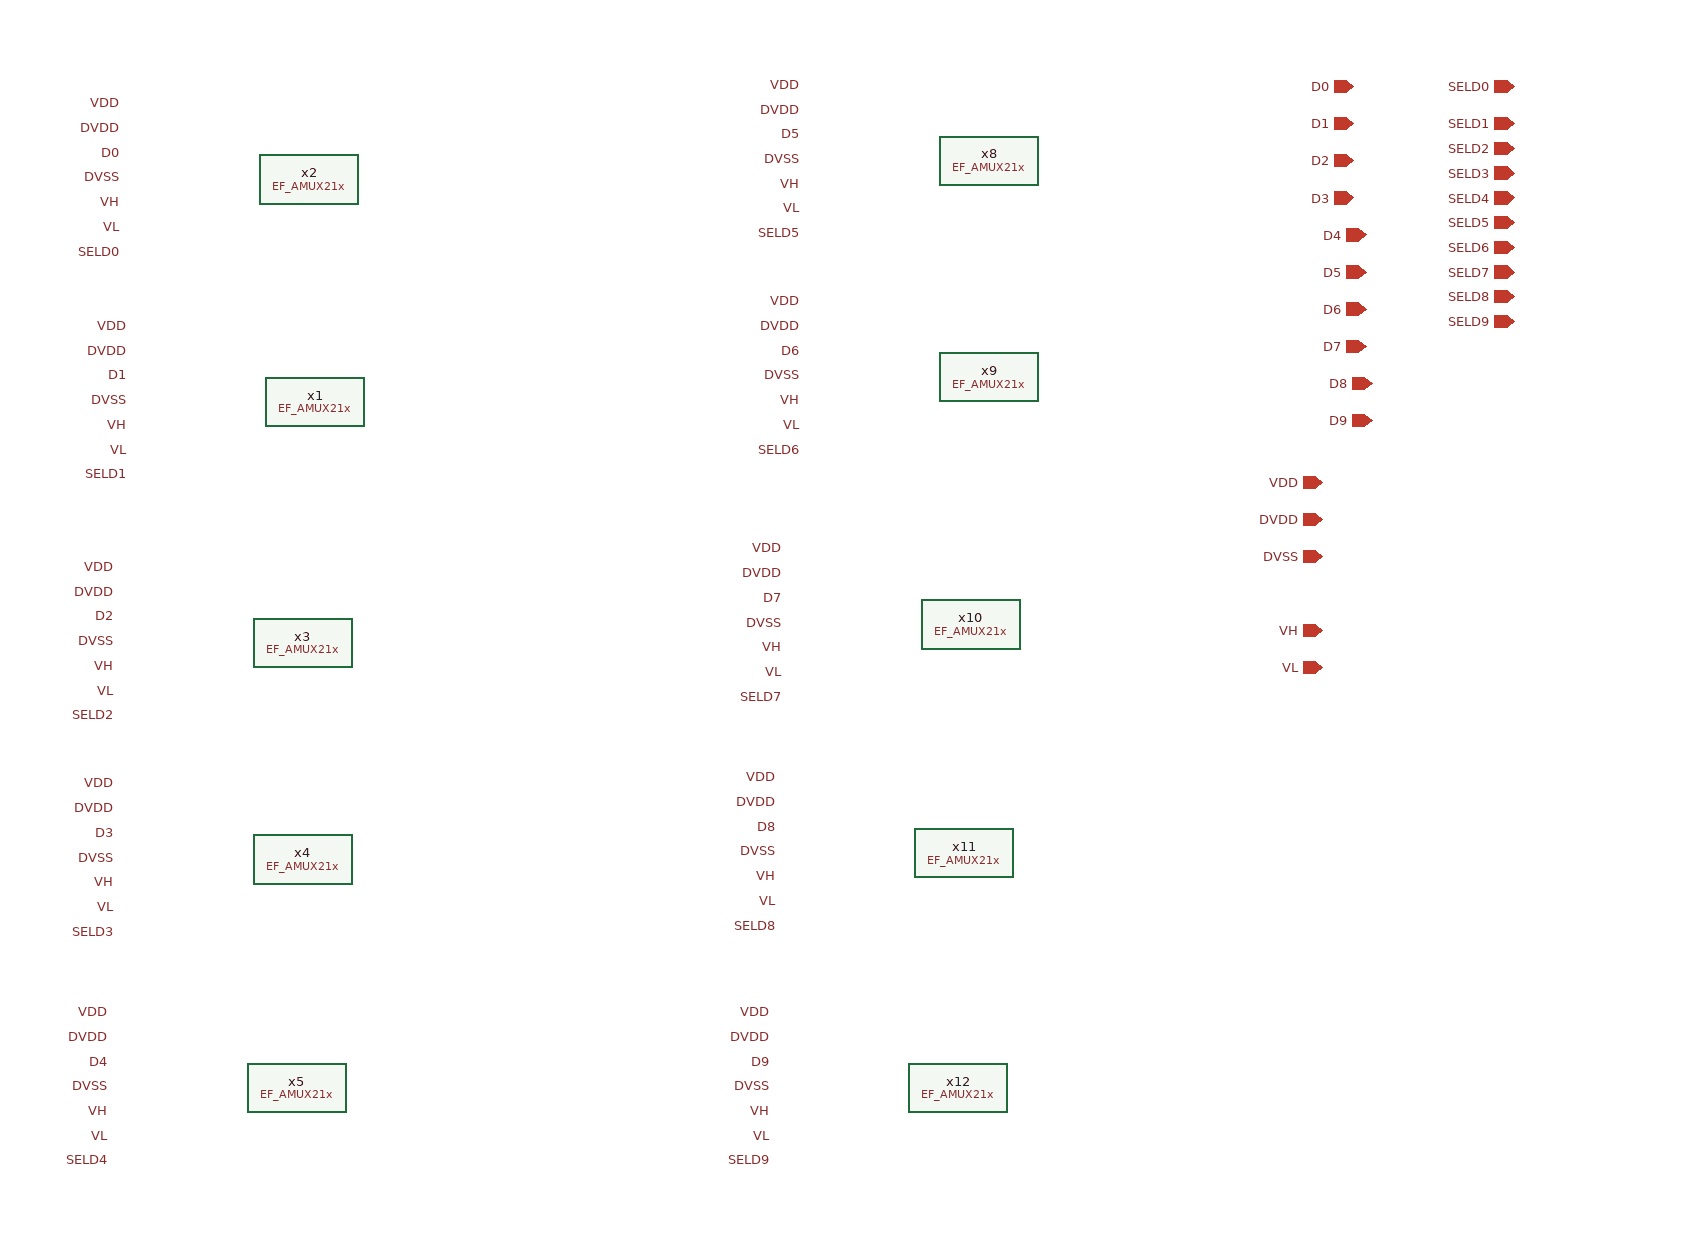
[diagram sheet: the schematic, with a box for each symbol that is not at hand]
v {xschem version=3.1.0 file_version=1.2
}
G {}
K {}
V {}
S {}
E {}
C {devices/lab_pin.sym} 1120 -965 0 0 {name=p6 sig_type=std_logic lab=VDD}
C {devices/lab_pin.sym} 1120 -945 0 0 {name=p8 sig_type=std_logic lab=DVDD}
C {Project/Package_IP/package_EF_ADCS1008NC/EF_ADCS1008NC/spice/xschem/EF_AMUX21x.sym} 1270 -905 0 0 {name=x2}
C {devices/lab_pin.sym} 1120 -925 0 0 {name=p17 sig_type=std_logic lab=D0}
C {devices/lab_pin.sym} 1120 -885 0 0 {name=p23 sig_type=std_logic lab=VH}
C {devices/lab_pin.sym} 1120 -845 0 0 {name=p11 sig_type=std_logic lab=SELD0}
C {devices/lab_pin.sym} 1120 -905 0 0 {name=p19 sig_type=std_logic lab=DVSS}
C {devices/lab_pin.sym} 1120 -865 0 0 {name=p22 sig_type=std_logic lab=VL}
C {devices/iopin.sym} 2090 -660 0 0 {name=p32 lab=VDD}
C {devices/iopin.sym} 2090 -630 0 0 {name=p33 lab=DVDD}
C {devices/iopin.sym} 2090 -600 0 0 {name=p34 lab=DVSS}
C {devices/iopin.sym} 2090 -540 0 0 {name=p36 lab=VH}
C {devices/lab_pin.sym} 1125 -785 0 0 {name=p12 sig_type=std_logic lab=VDD}
C {devices/lab_pin.sym} 1125 -765 0 0 {name=p13 sig_type=std_logic lab=DVDD}
C {Project/Package_IP/package_EF_ADCS1008NC/EF_ADCS1008NC/spice/xschem/EF_AMUX21x.sym} 1275 -725 0 0 {name=x1}
C {devices/lab_pin.sym} 1125 -745 0 0 {name=p14 sig_type=std_logic lab=D1}
C {devices/lab_pin.sym} 1125 -665 0 0 {name=p18 sig_type=std_logic lab=SELD1}
C {devices/lab_pin.sym} 1125 -725 0 0 {name=p20 sig_type=std_logic lab=DVSS}
C {devices/lab_pin.sym} 1125 -705 0 0 {name=p15 sig_type=std_logic lab=VH}
C {devices/lab_pin.sym} 1125 -685 0 0 {name=p26 sig_type=std_logic lab=VL}
C {devices/iopin.sym} 2090 -510 0 0 {name=p4 lab=VL}
C {devices/lab_pin.sym} 1115 -590 0 0 {name=p21 sig_type=std_logic lab=VDD}
C {devices/lab_pin.sym} 1115 -570 0 0 {name=p24 sig_type=std_logic lab=DVDD}
C {Project/Package_IP/package_EF_ADCS1008NC/EF_ADCS1008NC/spice/xschem/EF_AMUX21x.sym} 1265 -530 0 0 {name=x3}
C {devices/lab_pin.sym} 1115 -550 0 0 {name=p25 sig_type=std_logic lab=D2}
C {devices/lab_pin.sym} 1115 -470 0 0 {name=p28 sig_type=std_logic lab=SELD2}
C {devices/lab_pin.sym} 1115 -530 0 0 {name=p29 sig_type=std_logic lab=DVSS}
C {devices/lab_pin.sym} 1115 -510 0 0 {name=p5 sig_type=std_logic lab=VH}
C {devices/lab_pin.sym} 1115 -490 0 0 {name=p9 sig_type=std_logic lab=VL}
C {devices/lab_pin.sym} 1115 -415 0 0 {name=p7 sig_type=std_logic lab=VDD}
C {devices/lab_pin.sym} 1115 -395 0 0 {name=p10 sig_type=std_logic lab=DVDD}
C {Project/Package_IP/package_EF_ADCS1008NC/EF_ADCS1008NC/spice/xschem/EF_AMUX21x.sym} 1265 -355 0 0 {name=x4}
C {devices/lab_pin.sym} 1115 -375 0 0 {name=p30 sig_type=std_logic lab=D3}
C {devices/lab_pin.sym} 1115 -295 0 0 {name=p31 sig_type=std_logic lab=SELD3}
C {devices/lab_pin.sym} 1115 -355 0 0 {name=p35 sig_type=std_logic lab=DVSS}
C {devices/lab_pin.sym} 1115 -335 0 0 {name=p38 sig_type=std_logic lab=VH}
C {devices/lab_pin.sym} 1115 -315 0 0 {name=p39 sig_type=std_logic lab=VL}
C {devices/lab_pin.sym} 1110 -230 0 0 {name=p44 sig_type=std_logic lab=VDD}
C {devices/lab_pin.sym} 1110 -210 0 0 {name=p45 sig_type=std_logic lab=DVDD}
C {Project/Package_IP/package_EF_ADCS1008NC/EF_ADCS1008NC/spice/xschem/EF_AMUX21x.sym} 1260 -170 0 0 {name=x5}
C {devices/lab_pin.sym} 1110 -190 0 0 {name=p46 sig_type=std_logic lab=D4}
C {devices/lab_pin.sym} 1110 -110 0 0 {name=p47 sig_type=std_logic lab=SELD4}
C {devices/lab_pin.sym} 1110 -170 0 0 {name=p48 sig_type=std_logic lab=DVSS}
C {devices/lab_pin.sym} 1110 -150 0 0 {name=p49 sig_type=std_logic lab=VH}
C {devices/lab_pin.sym} 1110 -130 0 0 {name=p50 sig_type=std_logic lab=VL}
C {devices/lab_pin.sym} 1670 -980 0 0 {name=p74 sig_type=std_logic lab=VDD}
C {devices/lab_pin.sym} 1670 -960 0 0 {name=p75 sig_type=std_logic lab=DVDD}
C {Project/Package_IP/package_EF_ADCS1008NC/EF_ADCS1008NC/spice/xschem/EF_AMUX21x.sym} 1820 -920 0 0 {name=x8}
C {devices/lab_pin.sym} 1670 -940 0 0 {name=p76 sig_type=std_logic lab=D5}
C {devices/lab_pin.sym} 1670 -860 0 0 {name=p77 sig_type=std_logic lab=SELD5}
C {devices/lab_pin.sym} 1670 -920 0 0 {name=p78 sig_type=std_logic lab=DVSS}
C {devices/lab_pin.sym} 1670 -805 0 0 {name=p86 sig_type=std_logic lab=VDD}
C {devices/lab_pin.sym} 1670 -785 0 0 {name=p87 sig_type=std_logic lab=DVDD}
C {Project/Package_IP/package_EF_ADCS1008NC/EF_ADCS1008NC/spice/xschem/EF_AMUX21x.sym} 1820 -745 0 0 {name=x9}
C {devices/lab_pin.sym} 1670 -765 0 0 {name=p88 sig_type=std_logic lab=D6}
C {devices/lab_pin.sym} 1670 -685 0 0 {name=p89 sig_type=std_logic lab=SELD6}
C {devices/lab_pin.sym} 1670 -745 0 0 {name=p90 sig_type=std_logic lab=DVSS}
C {devices/lab_pin.sym} 1655 -605 0 0 {name=p96 sig_type=std_logic lab=VDD}
C {devices/lab_pin.sym} 1655 -585 0 0 {name=p97 sig_type=std_logic lab=DVDD}
C {Project/Package_IP/package_EF_ADCS1008NC/EF_ADCS1008NC/spice/xschem/EF_AMUX21x.sym} 1805 -545 0 0 {name=x10}
C {devices/lab_pin.sym} 1655 -565 0 0 {name=p98 sig_type=std_logic lab=D7}
C {devices/lab_pin.sym} 1655 -485 0 0 {name=p99 sig_type=std_logic lab=SELD7}
C {devices/lab_pin.sym} 1655 -545 0 0 {name=p100 sig_type=std_logic lab=DVSS}
C {devices/lab_pin.sym} 1650 -420 0 0 {name=p106 sig_type=std_logic lab=VDD}
C {devices/lab_pin.sym} 1650 -400 0 0 {name=p107 sig_type=std_logic lab=DVDD}
C {Project/Package_IP/package_EF_ADCS1008NC/EF_ADCS1008NC/spice/xschem/EF_AMUX21x.sym} 1800 -360 0 0 {name=x11}
C {devices/lab_pin.sym} 1650 -380 0 0 {name=p108 sig_type=std_logic lab=D8}
C {devices/lab_pin.sym} 1650 -300 0 0 {name=p109 sig_type=std_logic lab=SELD8}
C {devices/lab_pin.sym} 1650 -360 0 0 {name=p110 sig_type=std_logic lab=DVSS}
C {devices/lab_pin.sym} 1645 -230 0 0 {name=p116 sig_type=std_logic lab=VDD}
C {devices/lab_pin.sym} 1645 -210 0 0 {name=p117 sig_type=std_logic lab=DVDD}
C {Project/Package_IP/package_EF_ADCS1008NC/EF_ADCS1008NC/spice/xschem/EF_AMUX21x.sym} 1795 -170 0 0 {name=x12}
C {devices/lab_pin.sym} 1645 -190 0 0 {name=p118 sig_type=std_logic lab=D9}
C {devices/lab_pin.sym} 1645 -110 0 0 {name=p119 sig_type=std_logic lab=SELD9}
C {devices/lab_pin.sym} 1645 -170 0 0 {name=p120 sig_type=std_logic lab=DVSS}
C {devices/lab_pin.sym} 1670 -900 0 0 {name=p51 sig_type=std_logic lab=VH}
C {devices/lab_pin.sym} 1670 -880 0 0 {name=p52 sig_type=std_logic lab=VL}
C {devices/lab_pin.sym} 1670 -725 0 0 {name=p53 sig_type=std_logic lab=VH}
C {devices/lab_pin.sym} 1670 -705 0 0 {name=p54 sig_type=std_logic lab=VL}
C {devices/lab_pin.sym} 1655 -525 0 0 {name=p55 sig_type=std_logic lab=VH}
C {devices/lab_pin.sym} 1655 -505 0 0 {name=p56 sig_type=std_logic lab=VL}
C {devices/lab_pin.sym} 1650 -340 0 0 {name=p57 sig_type=std_logic lab=VH}
C {devices/lab_pin.sym} 1650 -320 0 0 {name=p58 sig_type=std_logic lab=VL}
C {devices/lab_pin.sym} 1645 -150 0 0 {name=p59 sig_type=std_logic lab=VH}
C {devices/lab_pin.sym} 1645 -130 0 0 {name=p60 sig_type=std_logic lab=VL}
C {devices/ipin.sym} 2115 -980 0 0 {name=p1 lab=D0}
C {devices/ipin.sym} 2115 -950 0 0 {name=p2 lab=D1}
C {devices/ipin.sym} 2115 -920 0 0 {name=p3 lab=D2}
C {devices/ipin.sym} 2115 -890 0 0 {name=p16 lab=D3}
C {devices/ipin.sym} 2125 -860 0 0 {name=p27 lab=D4}
C {devices/ipin.sym} 2125 -830 0 0 {name=p37 lab=D5}
C {devices/ipin.sym} 2125 -800 0 0 {name=p40 lab=D6}
C {devices/ipin.sym} 2125 -770 0 0 {name=p41 lab=D7}
C {devices/ipin.sym} 2130 -740 0 0 {name=p42 lab=D8}
C {devices/ipin.sym} 2130 -710 0 0 {name=p43 lab=D9}
C {devices/ipin.sym} 2245 -980 0 0 {name=p61 lab=SELD0}
C {devices/ipin.sym} 2245 -950 0 0 {name=p62 lab=SELD1}
C {devices/ipin.sym} 2245 -930 0 0 {name=p63 lab=SELD2}
C {devices/ipin.sym} 2245 -910 0 0 {name=p64 lab=SELD3}
C {devices/ipin.sym} 2245 -890 0 0 {name=p65 lab=SELD4}
C {devices/ipin.sym} 2245 -870 0 0 {name=p66 lab=SELD5}
C {devices/ipin.sym} 2245 -850 0 0 {name=p67 lab=SELD6}
C {devices/ipin.sym} 2245 -830 0 0 {name=p68 lab=SELD7}
C {devices/ipin.sym} 2245 -810 0 0 {name=p69 lab=SELD8}
C {devices/ipin.sym} 2245 -790 0 0 {name=p70 lab=SELD9}
